VERSION 5.7 ;
  NOWIREEXTENSIONATPIN ON ;
  DIVIDERCHAR "/" ;
  BUSBITCHARS "[]" ;
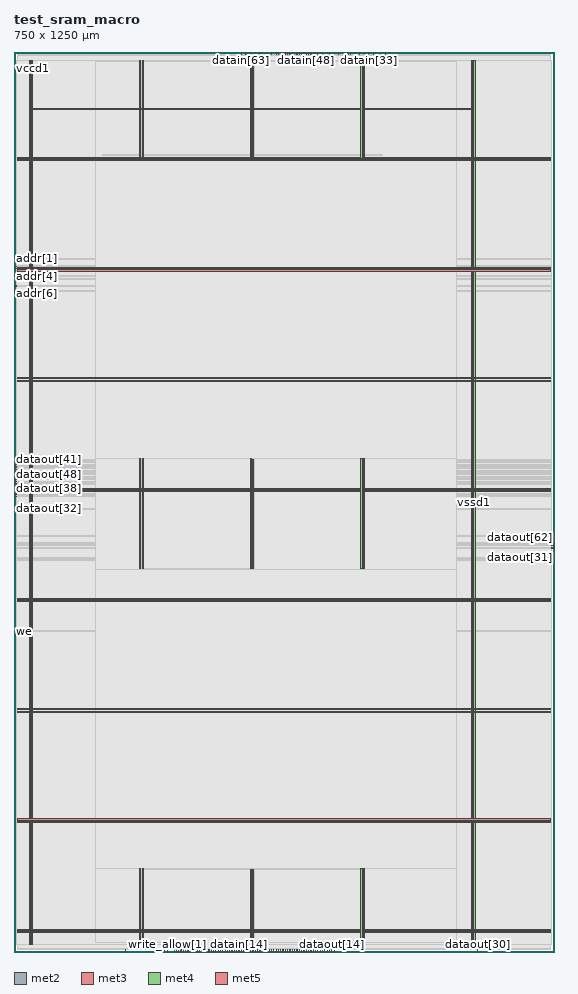
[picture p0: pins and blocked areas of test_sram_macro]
MACRO test_sram_macro
  CLASS BLOCK ;
  FOREIGN test_sram_macro ;
  ORIGIN 0.000 0.000 ;
  SIZE 750.000 BY 1250.000 ;
  PIN addr[0]
    DIRECTION INPUT ;
    USE SIGNAL ;
    ANTENNAGATEAREA 0.852000 ;
    PORT
      LAYER met2 ;
        RECT 202.950 0.000 203.230 4.000 ;
    END
  END addr[0]
  PIN addr[1]
    DIRECTION INPUT ;
    USE SIGNAL ;
    ANTENNAGATEAREA 0.495000 ;
    PORT
      LAYER met3 ;
        RECT 0.000 962.240 4.000 962.840 ;
    END
  END addr[1]
  PIN addr[2]
    DIRECTION INPUT ;
    USE SIGNAL ;
    ANTENNAGATEAREA 0.495000 ;
    PORT
      LAYER met3 ;
        RECT 0.000 952.040 4.000 952.640 ;
    END
  END addr[2]
  PIN addr[3]
    DIRECTION INPUT ;
    USE SIGNAL ;
    ANTENNAGATEAREA 0.495000 ;
    PORT
      LAYER met3 ;
        RECT 0.000 948.640 4.000 949.240 ;
    END
  END addr[3]
  PIN addr[4]
    DIRECTION INPUT ;
    USE SIGNAL ;
    ANTENNAGATEAREA 0.495000 ;
    PORT
      LAYER met3 ;
        RECT 0.000 938.440 4.000 939.040 ;
    END
  END addr[4]
  PIN addr[5]
    DIRECTION INPUT ;
    USE SIGNAL ;
    ANTENNAGATEAREA 0.495000 ;
    PORT
      LAYER met3 ;
        RECT 0.000 935.040 4.000 935.640 ;
    END
  END addr[5]
  PIN addr[6]
    DIRECTION INPUT ;
    USE SIGNAL ;
    ANTENNAGATEAREA 0.495000 ;
    PORT
      LAYER met3 ;
        RECT 0.000 924.840 4.000 925.440 ;
    END
  END addr[6]
  PIN addr[7]
    DIRECTION INPUT ;
    USE SIGNAL ;
    ANTENNAGATEAREA 0.495000 ;
    PORT
      LAYER met3 ;
        RECT 0.000 918.040 4.000 918.640 ;
    END
  END addr[7]
  PIN clk
    DIRECTION INPUT ;
    USE SIGNAL ;
    ANTENNAGATEAREA 0.852000 ;
    ANTENNADIFFAREA 0.434700 ;
    PORT
      LAYER met2 ;
        RECT 154.650 0.000 154.930 4.000 ;
    END
  END clk
  PIN cs
    DIRECTION INPUT ;
    USE SIGNAL ;
    ANTENNAGATEAREA 0.742500 ;
    PORT
      LAYER met2 ;
        RECT 444.450 0.000 444.730 4.000 ;
    END
  END cs
  PIN datain[0]
    DIRECTION INPUT ;
    USE SIGNAL ;
    ANTENNAGATEAREA 0.126000 ;
    PORT
      LAYER met2 ;
        RECT 228.710 0.000 228.990 4.000 ;
    END
  END datain[0]
  PIN datain[10]
    DIRECTION INPUT ;
    USE SIGNAL ;
    ANTENNAGATEAREA 0.213000 ;
    PORT
      LAYER met2 ;
        RECT 244.810 0.000 245.090 4.000 ;
    END
  END datain[10]
  PIN datain[11]
    DIRECTION INPUT ;
    USE SIGNAL ;
    ANTENNAGATEAREA 0.126000 ;
    PORT
      LAYER met2 ;
        RECT 289.890 0.000 290.170 4.000 ;
    END
  END datain[11]
  PIN datain[12]
    DIRECTION INPUT ;
    USE SIGNAL ;
    ANTENNAGATEAREA 0.126000 ;
    PORT
      LAYER met2 ;
        RECT 296.330 0.000 296.610 4.000 ;
    END
  END datain[12]
  PIN datain[13]
    DIRECTION INPUT ;
    USE SIGNAL ;
    ANTENNAGATEAREA 0.126000 ;
    PORT
      LAYER met2 ;
        RECT 302.770 0.000 303.050 4.000 ;
    END
  END datain[13]
  PIN datain[14]
    DIRECTION INPUT ;
    USE SIGNAL ;
    ANTENNAGATEAREA 0.126000 ;
    PORT
      LAYER met2 ;
        RECT 312.430 0.000 312.710 4.000 ;
    END
  END datain[14]
  PIN datain[15]
    DIRECTION INPUT ;
    USE SIGNAL ;
    ANTENNAGATEAREA 0.126000 ;
    PORT
      LAYER met2 ;
        RECT 318.870 0.000 319.150 4.000 ;
    END
  END datain[15]
  PIN datain[16]
    DIRECTION INPUT ;
    USE SIGNAL ;
    ANTENNAGATEAREA 0.126000 ;
    PORT
      LAYER met2 ;
        RECT 325.310 0.000 325.590 4.000 ;
    END
  END datain[16]
  PIN datain[17]
    DIRECTION INPUT ;
    USE SIGNAL ;
    ANTENNAGATEAREA 0.126000 ;
    PORT
      LAYER met2 ;
        RECT 331.750 0.000 332.030 4.000 ;
    END
  END datain[17]
  PIN datain[18]
    DIRECTION INPUT ;
    USE SIGNAL ;
    ANTENNAGATEAREA 0.126000 ;
    PORT
      LAYER met2 ;
        RECT 341.410 0.000 341.690 4.000 ;
    END
  END datain[18]
  PIN datain[19]
    DIRECTION INPUT ;
    USE SIGNAL ;
    ANTENNAGATEAREA 0.213000 ;
    PORT
      LAYER met2 ;
        RECT 354.290 0.000 354.570 4.000 ;
    END
  END datain[19]
  PIN datain[1]
    DIRECTION INPUT ;
    USE SIGNAL ;
    ANTENNAGATEAREA 0.126000 ;
    PORT
      LAYER met2 ;
        RECT 235.150 0.000 235.430 4.000 ;
    END
  END datain[1]
  PIN datain[20]
    DIRECTION INPUT ;
    USE SIGNAL ;
    ANTENNAGATEAREA 0.126000 ;
    PORT
      LAYER met2 ;
        RECT 351.070 0.000 351.350 4.000 ;
    END
  END datain[20]
  PIN datain[21]
    DIRECTION INPUT ;
    USE SIGNAL ;
    ANTENNAGATEAREA 0.213000 ;
    PORT
      LAYER met2 ;
        RECT 438.010 0.000 438.290 4.000 ;
    END
  END datain[21]
  PIN datain[22]
    DIRECTION INPUT ;
    USE SIGNAL ;
    ANTENNAGATEAREA 0.126000 ;
    PORT
      LAYER met2 ;
        RECT 360.730 0.000 361.010 4.000 ;
    END
  END datain[22]
  PIN datain[23]
    DIRECTION INPUT ;
    USE SIGNAL ;
    ANTENNAGATEAREA 0.126000 ;
    PORT
      LAYER met2 ;
        RECT 367.170 0.000 367.450 4.000 ;
    END
  END datain[23]
  PIN datain[24]
    DIRECTION INPUT ;
    USE SIGNAL ;
    ANTENNAGATEAREA 0.213000 ;
    PORT
      LAYER met2 ;
        RECT 383.270 0.000 383.550 4.000 ;
    END
  END datain[24]
  PIN datain[25]
    DIRECTION INPUT ;
    USE SIGNAL ;
    ANTENNAGATEAREA 0.126000 ;
    PORT
      LAYER met2 ;
        RECT 380.050 0.000 380.330 4.000 ;
    END
  END datain[25]
  PIN datain[26]
    DIRECTION INPUT ;
    USE SIGNAL ;
    ANTENNAGATEAREA 0.126000 ;
    PORT
      LAYER met2 ;
        RECT 386.490 0.000 386.770 4.000 ;
    END
  END datain[26]
  PIN datain[27]
    DIRECTION INPUT ;
    USE SIGNAL ;
    ANTENNAGATEAREA 0.213000 ;
    PORT
      LAYER met2 ;
        RECT 431.570 0.000 431.850 4.000 ;
    END
  END datain[27]
  PIN datain[28]
    DIRECTION INPUT ;
    USE SIGNAL ;
    ANTENNAGATEAREA 0.126000 ;
    PORT
      LAYER met2 ;
        RECT 396.150 0.000 396.430 4.000 ;
    END
  END datain[28]
  PIN datain[29]
    DIRECTION INPUT ;
    USE SIGNAL ;
    ANTENNAGATEAREA 0.126000 ;
    PORT
      LAYER met2 ;
        RECT 402.590 0.000 402.870 4.000 ;
    END
  END datain[29]
  PIN datain[2]
    DIRECTION INPUT ;
    USE SIGNAL ;
    ANTENNAGATEAREA 0.126000 ;
    PORT
      LAYER met2 ;
        RECT 241.590 0.000 241.870 4.000 ;
    END
  END datain[2]
  PIN datain[30]
    DIRECTION INPUT ;
    USE SIGNAL ;
    ANTENNAGATEAREA 0.126000 ;
    PORT
      LAYER met2 ;
        RECT 409.030 0.000 409.310 4.000 ;
    END
  END datain[30]
  PIN datain[31]
    DIRECTION INPUT ;
    USE SIGNAL ;
    ANTENNAGATEAREA 0.126000 ;
    PORT
      LAYER met2 ;
        RECT 418.690 0.000 418.970 4.000 ;
    END
  END datain[31]
  PIN datain[32]
    DIRECTION INPUT ;
    USE SIGNAL ;
    ANTENNAGATEAREA 0.213000 ;
    PORT
      LAYER met2 ;
        RECT 499.190 1246.000 499.470 1250.000 ;
    END
  END datain[32]
  PIN datain[33]
    DIRECTION INPUT ;
    USE SIGNAL ;
    ANTENNAGATEAREA 0.213000 ;
    PORT
      LAYER met2 ;
        RECT 492.750 1246.000 493.030 1250.000 ;
    END
  END datain[33]
  PIN datain[34]
    DIRECTION INPUT ;
    USE SIGNAL ;
    ANTENNAGATEAREA 0.213000 ;
    PORT
      LAYER met2 ;
        RECT 486.310 1246.000 486.590 1250.000 ;
    END
  END datain[34]
  PIN datain[35]
    DIRECTION INPUT ;
    USE SIGNAL ;
    ANTENNAGATEAREA 0.213000 ;
    PORT
      LAYER met2 ;
        RECT 479.870 1246.000 480.150 1250.000 ;
    END
  END datain[35]
  PIN datain[36]
    DIRECTION INPUT ;
    USE SIGNAL ;
    ANTENNAGATEAREA 0.213000 ;
    PORT
      LAYER met2 ;
        RECT 473.430 1246.000 473.710 1250.000 ;
    END
  END datain[36]
  PIN datain[37]
    DIRECTION INPUT ;
    USE SIGNAL ;
    ANTENNAGATEAREA 0.213000 ;
    PORT
      LAYER met2 ;
        RECT 466.990 1246.000 467.270 1250.000 ;
    END
  END datain[37]
  PIN datain[38]
    DIRECTION INPUT ;
    USE SIGNAL ;
    ANTENNAGATEAREA 0.213000 ;
    PORT
      LAYER met2 ;
        RECT 463.770 1246.000 464.050 1250.000 ;
    END
  END datain[38]
  PIN datain[39]
    DIRECTION INPUT ;
    USE SIGNAL ;
    ANTENNAGATEAREA 0.213000 ;
    PORT
      LAYER met2 ;
        RECT 457.330 1246.000 457.610 1250.000 ;
    END
  END datain[39]
  PIN datain[3]
    DIRECTION INPUT ;
    USE SIGNAL ;
    ANTENNAGATEAREA 0.126000 ;
    PORT
      LAYER met2 ;
        RECT 248.030 0.000 248.310 4.000 ;
    END
  END datain[3]
  PIN datain[40]
    DIRECTION INPUT ;
    USE SIGNAL ;
    ANTENNAGATEAREA 0.213000 ;
    PORT
      LAYER met2 ;
        RECT 450.890 1246.000 451.170 1250.000 ;
    END
  END datain[40]
  PIN datain[41]
    DIRECTION INPUT ;
    USE SIGNAL ;
    ANTENNAGATEAREA 0.213000 ;
    PORT
      LAYER met2 ;
        RECT 444.450 1246.000 444.730 1250.000 ;
    END
  END datain[41]
  PIN datain[42]
    DIRECTION INPUT ;
    USE SIGNAL ;
    ANTENNAGATEAREA 0.213000 ;
    PORT
      LAYER met2 ;
        RECT 438.010 1246.000 438.290 1250.000 ;
    END
  END datain[42]
  PIN datain[43]
    DIRECTION INPUT ;
    USE SIGNAL ;
    ANTENNAGATEAREA 0.213000 ;
    PORT
      LAYER met2 ;
        RECT 434.790 1246.000 435.070 1250.000 ;
    END
  END datain[43]
  PIN datain[44]
    DIRECTION INPUT ;
    USE SIGNAL ;
    ANTENNAGATEAREA 0.213000 ;
    PORT
      LAYER met2 ;
        RECT 428.350 1246.000 428.630 1250.000 ;
    END
  END datain[44]
  PIN datain[45]
    DIRECTION INPUT ;
    USE SIGNAL ;
    ANTENNAGATEAREA 0.213000 ;
    PORT
      LAYER met2 ;
        RECT 425.130 1246.000 425.410 1250.000 ;
    END
  END datain[45]
  PIN datain[46]
    DIRECTION INPUT ;
    USE SIGNAL ;
    ANTENNAGATEAREA 0.213000 ;
    PORT
      LAYER met2 ;
        RECT 421.910 1246.000 422.190 1250.000 ;
    END
  END datain[46]
  PIN datain[47]
    DIRECTION INPUT ;
    USE SIGNAL ;
    ANTENNAGATEAREA 0.213000 ;
    PORT
      LAYER met2 ;
        RECT 412.250 1246.000 412.530 1250.000 ;
    END
  END datain[47]
  PIN datain[48]
    DIRECTION INPUT ;
    USE SIGNAL ;
    ANTENNAGATEAREA 0.213000 ;
    PORT
      LAYER met2 ;
        RECT 405.810 1246.000 406.090 1250.000 ;
    END
  END datain[48]
  PIN datain[49]
    DIRECTION INPUT ;
    USE SIGNAL ;
    ANTENNAGATEAREA 0.213000 ;
    PORT
      LAYER met2 ;
        RECT 392.930 1246.000 393.210 1250.000 ;
    END
  END datain[49]
  PIN datain[4]
    DIRECTION INPUT ;
    USE SIGNAL ;
    ANTENNAGATEAREA 0.126000 ;
    PORT
      LAYER met2 ;
        RECT 254.470 0.000 254.750 4.000 ;
    END
  END datain[4]
  PIN datain[50]
    DIRECTION INPUT ;
    USE SIGNAL ;
    ANTENNAGATEAREA 0.213000 ;
    PORT
      LAYER met2 ;
        RECT 370.390 1246.000 370.670 1250.000 ;
    END
  END datain[50]
  PIN datain[51]
    DIRECTION INPUT ;
    USE SIGNAL ;
    ANTENNAGATEAREA 0.213000 ;
    PORT
      LAYER met2 ;
        RECT 380.050 1246.000 380.330 1250.000 ;
    END
  END datain[51]
  PIN datain[52]
    DIRECTION INPUT ;
    USE SIGNAL ;
    ANTENNAGATEAREA 0.213000 ;
    PORT
      LAYER met2 ;
        RECT 376.830 1246.000 377.110 1250.000 ;
    END
  END datain[52]
  PIN datain[53]
    DIRECTION INPUT ;
    USE SIGNAL ;
    ANTENNAGATEAREA 0.213000 ;
    PORT
      LAYER met2 ;
        RECT 373.610 1246.000 373.890 1250.000 ;
    END
  END datain[53]
  PIN datain[54]
    DIRECTION INPUT ;
    USE SIGNAL ;
    ANTENNAGATEAREA 0.213000 ;
    PORT
      LAYER met2 ;
        RECT 367.170 1246.000 367.450 1250.000 ;
    END
  END datain[54]
  PIN datain[55]
    DIRECTION INPUT ;
    USE SIGNAL ;
    ANTENNAGATEAREA 0.213000 ;
    PORT
      LAYER met2 ;
        RECT 363.950 1246.000 364.230 1250.000 ;
    END
  END datain[55]
  PIN datain[56]
    DIRECTION INPUT ;
    USE SIGNAL ;
    ANTENNAGATEAREA 0.213000 ;
    PORT
      LAYER met2 ;
        RECT 357.510 1246.000 357.790 1250.000 ;
    END
  END datain[56]
  PIN datain[57]
    DIRECTION INPUT ;
    USE SIGNAL ;
    ANTENNAGATEAREA 0.213000 ;
    PORT
      LAYER met2 ;
        RECT 351.070 1246.000 351.350 1250.000 ;
    END
  END datain[57]
  PIN datain[58]
    DIRECTION INPUT ;
    USE SIGNAL ;
    ANTENNAGATEAREA 0.213000 ;
    PORT
      LAYER met2 ;
        RECT 344.630 1246.000 344.910 1250.000 ;
    END
  END datain[58]
  PIN datain[59]
    DIRECTION INPUT ;
    USE SIGNAL ;
    ANTENNAGATEAREA 0.213000 ;
    PORT
      LAYER met2 ;
        RECT 341.410 1246.000 341.690 1250.000 ;
    END
  END datain[59]
  PIN datain[5]
    DIRECTION INPUT ;
    USE SIGNAL ;
    ANTENNAGATEAREA 0.126000 ;
    PORT
      LAYER met2 ;
        RECT 260.910 0.000 261.190 4.000 ;
    END
  END datain[5]
  PIN datain[60]
    DIRECTION INPUT ;
    USE SIGNAL ;
    ANTENNAGATEAREA 0.213000 ;
    PORT
      LAYER met2 ;
        RECT 334.970 1246.000 335.250 1250.000 ;
    END
  END datain[60]
  PIN datain[61]
    DIRECTION INPUT ;
    USE SIGNAL ;
    ANTENNAGATEAREA 0.213000 ;
    PORT
      LAYER met2 ;
        RECT 328.530 1246.000 328.810 1250.000 ;
    END
  END datain[61]
  PIN datain[62]
    DIRECTION INPUT ;
    USE SIGNAL ;
    ANTENNAGATEAREA 0.213000 ;
    PORT
      LAYER met2 ;
        RECT 322.090 1246.000 322.370 1250.000 ;
    END
  END datain[62]
  PIN datain[63]
    DIRECTION INPUT ;
    USE SIGNAL ;
    ANTENNAGATEAREA 0.213000 ;
    PORT
      LAYER met2 ;
        RECT 315.650 1246.000 315.930 1250.000 ;
    END
  END datain[63]
  PIN datain[6]
    DIRECTION INPUT ;
    USE SIGNAL ;
    ANTENNAGATEAREA 0.126000 ;
    PORT
      LAYER met2 ;
        RECT 264.130 0.000 264.410 4.000 ;
    END
  END datain[6]
  PIN datain[7]
    DIRECTION INPUT ;
    USE SIGNAL ;
    ANTENNAGATEAREA 0.126000 ;
    PORT
      LAYER met2 ;
        RECT 267.350 0.000 267.630 4.000 ;
    END
  END datain[7]
  PIN datain[8]
    DIRECTION INPUT ;
    USE SIGNAL ;
    ANTENNAGATEAREA 0.126000 ;
    PORT
      LAYER met2 ;
        RECT 273.790 0.000 274.070 4.000 ;
    END
  END datain[8]
  PIN datain[9]
    DIRECTION INPUT ;
    USE SIGNAL ;
    ANTENNAGATEAREA 0.126000 ;
    PORT
      LAYER met2 ;
        RECT 283.450 0.000 283.730 4.000 ;
    END
  END datain[9]
  PIN dataout[0]
    DIRECTION OUTPUT TRISTATE ;
    USE SIGNAL ;
    ANTENNADIFFAREA 0.795200 ;
    PORT
      LAYER met2 ;
        RECT 280.230 0.000 280.510 4.000 ;
    END
  END dataout[0]
  PIN dataout[10]
    DIRECTION OUTPUT TRISTATE ;
    USE SIGNAL ;
    ANTENNADIFFAREA 0.795200 ;
    PORT
      LAYER met2 ;
        RECT 334.970 0.000 335.250 4.000 ;
    END
  END dataout[10]
  PIN dataout[11]
    DIRECTION OUTPUT TRISTATE ;
    USE SIGNAL ;
    ANTENNADIFFAREA 0.795200 ;
    PORT
      LAYER met2 ;
        RECT 338.190 0.000 338.470 4.000 ;
    END
  END dataout[11]
  PIN dataout[12]
    DIRECTION OUTPUT TRISTATE ;
    USE SIGNAL ;
    ANTENNADIFFAREA 0.795200 ;
    PORT
      LAYER met2 ;
        RECT 344.630 0.000 344.910 4.000 ;
    END
  END dataout[12]
  PIN dataout[13]
    DIRECTION OUTPUT TRISTATE ;
    USE SIGNAL ;
    ANTENNADIFFAREA 0.795200 ;
    PORT
      LAYER met2 ;
        RECT 347.850 0.000 348.130 4.000 ;
    END
  END dataout[13]
  PIN dataout[14]
    DIRECTION OUTPUT TRISTATE ;
    USE SIGNAL ;
    ANTENNADIFFAREA 0.795200 ;
    PORT
      LAYER met2 ;
        RECT 441.230 0.000 441.510 4.000 ;
    END
  END dataout[14]
  PIN dataout[15]
    DIRECTION OUTPUT TRISTATE ;
    USE SIGNAL ;
    ANTENNADIFFAREA 0.795200 ;
    PORT
      LAYER met2 ;
        RECT 357.510 0.000 357.790 4.000 ;
    END
  END dataout[15]
  PIN dataout[16]
    DIRECTION OUTPUT TRISTATE ;
    USE SIGNAL ;
    ANTENNADIFFAREA 0.795200 ;
    PORT
      LAYER met2 ;
        RECT 363.950 0.000 364.230 4.000 ;
    END
  END dataout[16]
  PIN dataout[17]
    DIRECTION OUTPUT TRISTATE ;
    USE SIGNAL ;
    ANTENNADIFFAREA 0.795200 ;
    PORT
      LAYER met2 ;
        RECT 370.390 0.000 370.670 4.000 ;
    END
  END dataout[17]
  PIN dataout[18]
    DIRECTION OUTPUT TRISTATE ;
    USE SIGNAL ;
    ANTENNADIFFAREA 0.795200 ;
    PORT
      LAYER met2 ;
        RECT 373.610 0.000 373.890 4.000 ;
    END
  END dataout[18]
  PIN dataout[19]
    DIRECTION OUTPUT TRISTATE ;
    USE SIGNAL ;
    ANTENNADIFFAREA 0.795200 ;
    PORT
      LAYER met2 ;
        RECT 376.830 0.000 377.110 4.000 ;
    END
  END dataout[19]
  PIN dataout[1]
    DIRECTION OUTPUT TRISTATE ;
    USE SIGNAL ;
    ANTENNADIFFAREA 0.795200 ;
    PORT
      LAYER met2 ;
        RECT 270.570 0.000 270.850 4.000 ;
    END
  END dataout[1]
  PIN dataout[20]
    DIRECTION OUTPUT TRISTATE ;
    USE SIGNAL ;
    ANTENNADIFFAREA 0.795200 ;
    PORT
      LAYER met2 ;
        RECT 389.710 0.000 389.990 4.000 ;
    END
  END dataout[20]
  PIN dataout[21]
    DIRECTION OUTPUT TRISTATE ;
    USE SIGNAL ;
    ANTENNADIFFAREA 0.795200 ;
    PORT
      LAYER met2 ;
        RECT 392.930 0.000 393.210 4.000 ;
    END
  END dataout[21]
  PIN dataout[22]
    DIRECTION OUTPUT TRISTATE ;
    USE SIGNAL ;
    ANTENNADIFFAREA 0.795200 ;
    PORT
      LAYER met2 ;
        RECT 399.370 0.000 399.650 4.000 ;
    END
  END dataout[22]
  PIN dataout[23]
    DIRECTION OUTPUT TRISTATE ;
    USE SIGNAL ;
    ANTENNADIFFAREA 0.795200 ;
    PORT
      LAYER met2 ;
        RECT 405.810 0.000 406.090 4.000 ;
    END
  END dataout[23]
  PIN dataout[24]
    DIRECTION OUTPUT TRISTATE ;
    USE SIGNAL ;
    ANTENNADIFFAREA 0.795200 ;
    PORT
      LAYER met2 ;
        RECT 412.250 0.000 412.530 4.000 ;
    END
  END dataout[24]
  PIN dataout[25]
    DIRECTION OUTPUT TRISTATE ;
    USE SIGNAL ;
    ANTENNADIFFAREA 0.795200 ;
    PORT
      LAYER met2 ;
        RECT 415.470 0.000 415.750 4.000 ;
    END
  END dataout[25]
  PIN dataout[26]
    DIRECTION OUTPUT TRISTATE ;
    USE SIGNAL ;
    ANTENNADIFFAREA 0.795200 ;
    PORT
      LAYER met2 ;
        RECT 421.910 0.000 422.190 4.000 ;
    END
  END dataout[26]
  PIN dataout[27]
    DIRECTION OUTPUT TRISTATE ;
    USE SIGNAL ;
    ANTENNADIFFAREA 0.795200 ;
    PORT
      LAYER met2 ;
        RECT 428.350 0.000 428.630 4.000 ;
    END
  END dataout[27]
  PIN dataout[28]
    DIRECTION OUTPUT TRISTATE ;
    USE SIGNAL ;
    ANTENNADIFFAREA 0.795200 ;
    PORT
      LAYER met2 ;
        RECT 425.130 0.000 425.410 4.000 ;
    END
  END dataout[28]
  PIN dataout[29]
    DIRECTION OUTPUT TRISTATE ;
    USE SIGNAL ;
    ANTENNADIFFAREA 0.795200 ;
    PORT
      LAYER met2 ;
        RECT 434.790 0.000 435.070 4.000 ;
    END
  END dataout[29]
  PIN dataout[2]
    DIRECTION OUTPUT TRISTATE ;
    USE SIGNAL ;
    ANTENNADIFFAREA 0.795200 ;
    PORT
      LAYER met2 ;
        RECT 277.010 0.000 277.290 4.000 ;
    END
  END dataout[2]
  PIN dataout[30]
    DIRECTION OUTPUT TRISTATE ;
    USE SIGNAL ;
    ANTENNADIFFAREA 0.795200 ;
    PORT
      LAYER met2 ;
        RECT 644.090 0.000 644.370 4.000 ;
    END
  END dataout[30]
  PIN dataout[31]
    DIRECTION OUTPUT TRISTATE ;
    USE SIGNAL ;
    ANTENNADIFFAREA 0.445500 ;
    PORT
      LAYER met3 ;
        RECT 746.000 547.440 750.000 548.040 ;
    END
  END dataout[31]
  PIN dataout[32]
    DIRECTION OUTPUT TRISTATE ;
    USE SIGNAL ;
    ANTENNADIFFAREA 0.795200 ;
    PORT
      LAYER met3 ;
        RECT 0.000 615.440 4.000 616.040 ;
    END
  END dataout[32]
  PIN dataout[33]
    DIRECTION OUTPUT TRISTATE ;
    USE SIGNAL ;
    ANTENNADIFFAREA 0.795200 ;
    PORT
      LAYER met2 ;
        RECT 257.690 0.000 257.970 4.000 ;
    END
  END dataout[33]
  PIN dataout[34]
    DIRECTION OUTPUT TRISTATE ;
    USE SIGNAL ;
    ANTENNADIFFAREA 0.795200 ;
    PORT
      LAYER met2 ;
        RECT 238.370 0.000 238.650 4.000 ;
    END
  END dataout[34]
  PIN dataout[35]
    DIRECTION OUTPUT TRISTATE ;
    USE SIGNAL ;
    ANTENNADIFFAREA 0.795200 ;
    PORT
      LAYER met2 ;
        RECT 231.930 0.000 232.210 4.000 ;
    END
  END dataout[35]
  PIN dataout[36]
    DIRECTION OUTPUT TRISTATE ;
    USE SIGNAL ;
    ANTENNADIFFAREA 0.795200 ;
    PORT
      LAYER met2 ;
        RECT 322.090 0.000 322.370 4.000 ;
    END
  END dataout[36]
  PIN dataout[37]
    DIRECTION OUTPUT TRISTATE ;
    USE SIGNAL ;
    ANTENNADIFFAREA 0.795200 ;
    PORT
      LAYER met2 ;
        RECT 328.530 0.000 328.810 4.000 ;
    END
  END dataout[37]
  PIN dataout[38]
    DIRECTION OUTPUT TRISTATE ;
    USE SIGNAL ;
    ANTENNADIFFAREA 0.795200 ;
    PORT
      LAYER met3 ;
        RECT 0.000 632.440 4.000 633.040 ;
    END
  END dataout[38]
  PIN dataout[39]
    DIRECTION OUTPUT TRISTATE ;
    USE SIGNAL ;
    ANTENNADIFFAREA 0.795200 ;
    PORT
      LAYER met3 ;
        RECT 0.000 635.840 4.000 636.440 ;
    END
  END dataout[39]
  PIN dataout[3]
    DIRECTION OUTPUT TRISTATE ;
    USE SIGNAL ;
    ANTENNADIFFAREA 0.795200 ;
    PORT
      LAYER met2 ;
        RECT 286.670 0.000 286.950 4.000 ;
    END
  END dataout[3]
  PIN dataout[40]
    DIRECTION OUTPUT TRISTATE ;
    USE SIGNAL ;
    ANTENNADIFFAREA 0.795200 ;
    PORT
      LAYER met3 ;
        RECT 0.000 649.440 4.000 650.040 ;
    END
  END dataout[40]
  PIN dataout[41]
    DIRECTION OUTPUT TRISTATE ;
    USE SIGNAL ;
    ANTENNADIFFAREA 0.795200 ;
    PORT
      LAYER met3 ;
        RECT 0.000 683.440 4.000 684.040 ;
    END
  END dataout[41]
  PIN dataout[42]
    DIRECTION OUTPUT TRISTATE ;
    USE SIGNAL ;
    ANTENNADIFFAREA 0.795200 ;
    PORT
      LAYER met3 ;
        RECT 0.000 680.040 4.000 680.640 ;
    END
  END dataout[42]
  PIN dataout[43]
    DIRECTION OUTPUT TRISTATE ;
    USE SIGNAL ;
    ANTENNADIFFAREA 0.795200 ;
    PORT
      LAYER met3 ;
        RECT 0.000 669.840 4.000 670.440 ;
    END
  END dataout[43]
  PIN dataout[44]
    DIRECTION OUTPUT TRISTATE ;
    USE SIGNAL ;
    ANTENNADIFFAREA 0.795200 ;
    PORT
      LAYER met3 ;
        RECT 0.000 673.240 4.000 673.840 ;
    END
  END dataout[44]
  PIN dataout[45]
    DIRECTION OUTPUT TRISTATE ;
    USE SIGNAL ;
    ANTENNADIFFAREA 0.795200 ;
    PORT
      LAYER met3 ;
        RECT 0.000 676.640 4.000 677.240 ;
    END
  END dataout[45]
  PIN dataout[46]
    DIRECTION OUTPUT TRISTATE ;
    USE SIGNAL ;
    ANTENNADIFFAREA 0.795200 ;
    PORT
      LAYER met3 ;
        RECT 0.000 666.440 4.000 667.040 ;
    END
  END dataout[46]
  PIN dataout[47]
    DIRECTION OUTPUT TRISTATE ;
    USE SIGNAL ;
    ANTENNADIFFAREA 0.795200 ;
    PORT
      LAYER met3 ;
        RECT 0.000 659.640 4.000 660.240 ;
    END
  END dataout[47]
  PIN dataout[48]
    DIRECTION OUTPUT TRISTATE ;
    USE SIGNAL ;
    ANTENNADIFFAREA 0.795200 ;
    PORT
      LAYER met3 ;
        RECT 0.000 663.040 4.000 663.640 ;
    END
  END dataout[48]
  PIN dataout[49]
    DIRECTION OUTPUT TRISTATE ;
    USE SIGNAL ;
    ANTENNADIFFAREA 0.795200 ;
    PORT
      LAYER met3 ;
        RECT 0.000 656.240 4.000 656.840 ;
    END
  END dataout[49]
  PIN dataout[4]
    DIRECTION OUTPUT TRISTATE ;
    USE SIGNAL ;
    ANTENNADIFFAREA 0.795200 ;
    PORT
      LAYER met2 ;
        RECT 293.110 0.000 293.390 4.000 ;
    END
  END dataout[4]
  PIN dataout[50]
    DIRECTION OUTPUT TRISTATE ;
    USE SIGNAL ;
    ANTENNADIFFAREA 0.795200 ;
    PORT
      LAYER met3 ;
        RECT 0.000 652.840 4.000 653.440 ;
    END
  END dataout[50]
  PIN dataout[51]
    DIRECTION OUTPUT TRISTATE ;
    USE SIGNAL ;
    ANTENNADIFFAREA 0.795200 ;
    PORT
      LAYER met2 ;
        RECT 386.490 1246.000 386.770 1250.000 ;
    END
  END dataout[51]
  PIN dataout[52]
    DIRECTION OUTPUT TRISTATE ;
    USE SIGNAL ;
    ANTENNADIFFAREA 0.795200 ;
    PORT
      LAYER met2 ;
        RECT 389.710 1246.000 389.990 1250.000 ;
    END
  END dataout[52]
  PIN dataout[53]
    DIRECTION OUTPUT TRISTATE ;
    USE SIGNAL ;
    ANTENNADIFFAREA 0.795200 ;
    PORT
      LAYER met2 ;
        RECT 383.270 1246.000 383.550 1250.000 ;
    END
  END dataout[53]
  PIN dataout[54]
    DIRECTION OUTPUT TRISTATE ;
    USE SIGNAL ;
    ANTENNADIFFAREA 0.795200 ;
    PORT
      LAYER met2 ;
        RECT 402.590 1246.000 402.870 1250.000 ;
    END
  END dataout[54]
  PIN dataout[55]
    DIRECTION OUTPUT TRISTATE ;
    USE SIGNAL ;
    ANTENNADIFFAREA 0.795200 ;
    PORT
      LAYER met2 ;
        RECT 399.370 1246.000 399.650 1250.000 ;
    END
  END dataout[55]
  PIN dataout[56]
    DIRECTION OUTPUT TRISTATE ;
    USE SIGNAL ;
    ANTENNADIFFAREA 0.795200 ;
    PORT
      LAYER met2 ;
        RECT 396.150 1246.000 396.430 1250.000 ;
    END
  END dataout[56]
  PIN dataout[57]
    DIRECTION OUTPUT TRISTATE ;
    USE SIGNAL ;
    ANTENNADIFFAREA 0.795200 ;
    PORT
      LAYER met2 ;
        RECT 409.030 1246.000 409.310 1250.000 ;
    END
  END dataout[57]
  PIN dataout[58]
    DIRECTION OUTPUT TRISTATE ;
    USE SIGNAL ;
    ANTENNADIFFAREA 0.795200 ;
    PORT
      LAYER met2 ;
        RECT 418.690 1246.000 418.970 1250.000 ;
    END
  END dataout[58]
  PIN dataout[59]
    DIRECTION OUTPUT TRISTATE ;
    USE SIGNAL ;
    ANTENNADIFFAREA 0.795200 ;
    PORT
      LAYER met2 ;
        RECT 415.470 1246.000 415.750 1250.000 ;
    END
  END dataout[59]
  PIN dataout[5]
    DIRECTION OUTPUT TRISTATE ;
    USE SIGNAL ;
    ANTENNADIFFAREA 0.795200 ;
    PORT
      LAYER met2 ;
        RECT 299.550 0.000 299.830 4.000 ;
    END
  END dataout[5]
  PIN dataout[60]
    DIRECTION OUTPUT TRISTATE ;
    USE SIGNAL ;
    ANTENNADIFFAREA 0.795200 ;
    PORT
      LAYER met3 ;
        RECT 746.000 578.040 750.000 578.640 ;
    END
  END dataout[60]
  PIN dataout[61]
    DIRECTION OUTPUT TRISTATE ;
    USE SIGNAL ;
    ANTENNADIFFAREA 0.445500 ;
    PORT
      LAYER met3 ;
        RECT 746.000 567.840 750.000 568.440 ;
    END
  END dataout[61]
  PIN dataout[62]
    DIRECTION OUTPUT TRISTATE ;
    USE SIGNAL ;
    ANTENNADIFFAREA 0.795200 ;
    PORT
      LAYER met3 ;
        RECT 746.000 564.440 750.000 565.040 ;
    END
  END dataout[62]
  PIN dataout[63]
    DIRECTION OUTPUT TRISTATE ;
    USE SIGNAL ;
    ANTENNADIFFAREA 0.445500 ;
    PORT
      LAYER met3 ;
        RECT 746.000 561.040 750.000 561.640 ;
    END
  END dataout[63]
  PIN dataout[6]
    DIRECTION OUTPUT TRISTATE ;
    USE SIGNAL ;
    ANTENNADIFFAREA 0.795200 ;
    PORT
      LAYER met2 ;
        RECT 305.990 0.000 306.270 4.000 ;
    END
  END dataout[6]
  PIN dataout[7]
    DIRECTION OUTPUT TRISTATE ;
    USE SIGNAL ;
    ANTENNADIFFAREA 0.795200 ;
    PORT
      LAYER met2 ;
        RECT 309.210 0.000 309.490 4.000 ;
    END
  END dataout[7]
  PIN dataout[8]
    DIRECTION OUTPUT TRISTATE ;
    USE SIGNAL ;
    ANTENNADIFFAREA 0.795200 ;
    PORT
      LAYER met2 ;
        RECT 251.250 0.000 251.530 4.000 ;
    END
  END dataout[8]
  PIN dataout[9]
    DIRECTION OUTPUT TRISTATE ;
    USE SIGNAL ;
    ANTENNADIFFAREA 0.795200 ;
    PORT
      LAYER met2 ;
        RECT 315.650 0.000 315.930 4.000 ;
    END
  END dataout[9]
  PIN rst_n
    DIRECTION INPUT ;
    USE SIGNAL ;
    ANTENNAGATEAREA 0.213000 ;
    PORT
      LAYER met3 ;
        RECT 746.000 544.040 750.000 544.640 ;
    END
  END rst_n
  PIN vccd1
    DIRECTION INOUT ;
    USE POWER ;
    PORT
      LAYER met4 ;
        RECT 21.040 10.640 22.640 1237.840 ;
    END
    PORT
      LAYER met4 ;
        RECT 174.640 10.640 176.240 115.320 ;
    END
    PORT
      LAYER met4 ;
        RECT 174.640 532.180 176.240 685.320 ;
    END
    PORT
      LAYER met4 ;
        RECT 174.640 1102.180 176.240 1237.840 ;
    END
    PORT
      LAYER met4 ;
        RECT 328.240 10.640 329.840 114.400 ;
    END
    PORT
      LAYER met4 ;
        RECT 328.240 533.100 329.840 685.320 ;
    END
    PORT
      LAYER met4 ;
        RECT 328.240 1103.100 329.840 1237.840 ;
    END
    PORT
      LAYER met4 ;
        RECT 481.840 10.640 483.440 115.320 ;
    END
    PORT
      LAYER met4 ;
        RECT 481.840 532.180 483.440 685.320 ;
    END
    PORT
      LAYER met4 ;
        RECT 481.840 1102.180 483.440 1237.840 ;
    END
    PORT
      LAYER met4 ;
        RECT 635.440 10.640 637.040 1237.840 ;
    END
    PORT
      LAYER met5 ;
        RECT 5.280 26.730 744.520 28.330 ;
    END
    PORT
      LAYER met5 ;
        RECT 5.280 179.910 744.520 181.510 ;
    END
    PORT
      LAYER met5 ;
        RECT 5.280 333.090 744.520 334.690 ;
    END
    PORT
      LAYER met5 ;
        RECT 5.280 486.270 744.520 487.870 ;
    END
    PORT
      LAYER met5 ;
        RECT 5.280 639.450 744.520 641.050 ;
    END
    PORT
      LAYER met5 ;
        RECT 5.280 792.630 744.520 794.230 ;
    END
    PORT
      LAYER met5 ;
        RECT 5.280 945.810 744.520 947.410 ;
    END
    PORT
      LAYER met5 ;
        RECT 5.280 1098.990 744.520 1100.590 ;
    END
    PORT
      LAYER met5 ;
        RECT 21.040 1170.500 637.040 1172.100 ;
    END
  END vccd1
  PIN vssd1
    DIRECTION INOUT ;
    USE GROUND ;
    PORT
      LAYER met4 ;
        RECT 24.340 10.640 25.940 1237.840 ;
    END
    PORT
      LAYER met4 ;
        RECT 177.940 10.640 179.540 115.320 ;
    END
    PORT
      LAYER met4 ;
        RECT 177.940 532.180 179.540 685.320 ;
    END
    PORT
      LAYER met4 ;
        RECT 177.940 1102.180 179.540 1237.840 ;
    END
    PORT
      LAYER met4 ;
        RECT 331.540 10.640 333.140 114.480 ;
    END
    PORT
      LAYER met4 ;
        RECT 331.540 532.180 333.140 684.400 ;
    END
    PORT
      LAYER met4 ;
        RECT 331.540 1103.100 333.140 1237.840 ;
    END
    PORT
      LAYER met4 ;
        RECT 485.140 10.640 486.740 115.320 ;
    END
    PORT
      LAYER met4 ;
        RECT 485.140 532.180 486.740 685.320 ;
    END
    PORT
      LAYER met4 ;
        RECT 485.140 1103.100 486.740 1237.840 ;
    END
    PORT
      LAYER met4 ;
        RECT 638.740 10.640 640.340 1237.840 ;
    END
    PORT
      LAYER met5 ;
        RECT 5.280 30.030 744.520 31.630 ;
    END
    PORT
      LAYER met5 ;
        RECT 5.280 183.210 744.520 184.810 ;
    END
    PORT
      LAYER met5 ;
        RECT 5.280 336.390 744.520 337.990 ;
    END
    PORT
      LAYER met5 ;
        RECT 5.280 489.570 744.520 491.170 ;
    END
    PORT
      LAYER met5 ;
        RECT 5.280 642.750 744.520 644.350 ;
    END
    PORT
      LAYER met5 ;
        RECT 5.280 795.930 744.520 797.530 ;
    END
    PORT
      LAYER met5 ;
        RECT 5.280 949.110 744.520 950.710 ;
    END
    PORT
      LAYER met5 ;
        RECT 5.280 1102.290 744.520 1103.890 ;
    END
  END vssd1
  PIN we
    DIRECTION INPUT ;
    USE SIGNAL ;
    ANTENNAGATEAREA 0.159000 ;
    PORT
      LAYER met3 ;
        RECT 0.000 445.440 4.000 446.040 ;
    END
  END we
  PIN write_allow[0]
    DIRECTION INPUT ;
    USE SIGNAL ;
    ANTENNAGATEAREA 0.126000 ;
    PORT
      LAYER met2 ;
        RECT 209.390 0.000 209.670 4.000 ;
    END
  END write_allow[0]
  PIN write_allow[1]
    DIRECTION INPUT ;
    USE SIGNAL ;
    ANTENNAGATEAREA 0.126000 ;
    PORT
      LAYER met2 ;
        RECT 212.610 0.000 212.890 4.000 ;
    END
  END write_allow[1]
  PIN write_allow[2]
    DIRECTION INPUT ;
    USE SIGNAL ;
    ANTENNAGATEAREA 0.126000 ;
    PORT
      LAYER met2 ;
        RECT 222.270 0.000 222.550 4.000 ;
    END
  END write_allow[2]
  PIN write_allow[3]
    DIRECTION INPUT ;
    USE SIGNAL ;
    ANTENNAGATEAREA 0.126000 ;
    PORT
      LAYER met2 ;
        RECT 225.490 0.000 225.770 4.000 ;
    END
  END write_allow[3]
  PIN write_allow[4]
    DIRECTION INPUT ;
    USE SIGNAL ;
    ANTENNAGATEAREA 0.213000 ;
    PORT
      LAYER met2 ;
        RECT 521.730 1246.000 522.010 1250.000 ;
    END
  END write_allow[4]
  PIN write_allow[5]
    DIRECTION INPUT ;
    USE SIGNAL ;
    ANTENNAGATEAREA 0.213000 ;
    PORT
      LAYER met2 ;
        RECT 515.290 1246.000 515.570 1250.000 ;
    END
  END write_allow[5]
  PIN write_allow[6]
    DIRECTION INPUT ;
    USE SIGNAL ;
    ANTENNAGATEAREA 0.213000 ;
    PORT
      LAYER met2 ;
        RECT 508.850 1246.000 509.130 1250.000 ;
    END
  END write_allow[6]
  PIN write_allow[7]
    DIRECTION INPUT ;
    USE SIGNAL ;
    ANTENNAGATEAREA 0.213000 ;
    PORT
      LAYER met2 ;
        RECT 502.410 1246.000 502.690 1250.000 ;
    END
  END write_allow[7]
  OBS
      LAYER li1 ;
        RECT 5.520 10.795 744.280 1237.685 ;
      LAYER met1 ;
        RECT 4.670 10.640 745.130 1237.840 ;
      LAYER met2 ;
        RECT 4.690 1245.720 315.370 1246.170 ;
        RECT 316.210 1245.720 321.810 1246.170 ;
        RECT 322.650 1245.720 328.250 1246.170 ;
        RECT 329.090 1245.720 334.690 1246.170 ;
        RECT 335.530 1245.720 341.130 1246.170 ;
        RECT 341.970 1245.720 344.350 1246.170 ;
        RECT 345.190 1245.720 350.790 1246.170 ;
        RECT 351.630 1245.720 357.230 1246.170 ;
        RECT 358.070 1245.720 363.670 1246.170 ;
        RECT 364.510 1245.720 366.890 1246.170 ;
        RECT 367.730 1245.720 370.110 1246.170 ;
        RECT 370.950 1245.720 373.330 1246.170 ;
        RECT 374.170 1245.720 376.550 1246.170 ;
        RECT 377.390 1245.720 379.770 1246.170 ;
        RECT 380.610 1245.720 382.990 1246.170 ;
        RECT 383.830 1245.720 386.210 1246.170 ;
        RECT 387.050 1245.720 389.430 1246.170 ;
        RECT 390.270 1245.720 392.650 1246.170 ;
        RECT 393.490 1245.720 395.870 1246.170 ;
        RECT 396.710 1245.720 399.090 1246.170 ;
        RECT 399.930 1245.720 402.310 1246.170 ;
        RECT 403.150 1245.720 405.530 1246.170 ;
        RECT 406.370 1245.720 408.750 1246.170 ;
        RECT 409.590 1245.720 411.970 1246.170 ;
        RECT 412.810 1245.720 415.190 1246.170 ;
        RECT 416.030 1245.720 418.410 1246.170 ;
        RECT 419.250 1245.720 421.630 1246.170 ;
        RECT 422.470 1245.720 424.850 1246.170 ;
        RECT 425.690 1245.720 428.070 1246.170 ;
        RECT 428.910 1245.720 434.510 1246.170 ;
        RECT 435.350 1245.720 437.730 1246.170 ;
        RECT 438.570 1245.720 444.170 1246.170 ;
        RECT 445.010 1245.720 450.610 1246.170 ;
        RECT 451.450 1245.720 457.050 1246.170 ;
        RECT 457.890 1245.720 463.490 1246.170 ;
        RECT 464.330 1245.720 466.710 1246.170 ;
        RECT 467.550 1245.720 473.150 1246.170 ;
        RECT 473.990 1245.720 479.590 1246.170 ;
        RECT 480.430 1245.720 486.030 1246.170 ;
        RECT 486.870 1245.720 492.470 1246.170 ;
        RECT 493.310 1245.720 498.910 1246.170 ;
        RECT 499.750 1245.720 502.130 1246.170 ;
        RECT 502.970 1245.720 508.570 1246.170 ;
        RECT 509.410 1245.720 515.010 1246.170 ;
        RECT 515.850 1245.720 521.450 1246.170 ;
        RECT 522.290 1245.720 745.110 1246.170 ;
        RECT 4.690 4.280 745.110 1245.720 ;
        RECT 4.690 3.670 154.370 4.280 ;
        RECT 155.210 3.670 202.670 4.280 ;
        RECT 203.510 3.670 209.110 4.280 ;
        RECT 209.950 3.670 212.330 4.280 ;
        RECT 213.170 3.670 221.990 4.280 ;
        RECT 222.830 3.670 225.210 4.280 ;
        RECT 226.050 3.670 228.430 4.280 ;
        RECT 229.270 3.670 231.650 4.280 ;
        RECT 232.490 3.670 234.870 4.280 ;
        RECT 235.710 3.670 238.090 4.280 ;
        RECT 238.930 3.670 241.310 4.280 ;
        RECT 242.150 3.670 244.530 4.280 ;
        RECT 245.370 3.670 247.750 4.280 ;
        RECT 248.590 3.670 250.970 4.280 ;
        RECT 251.810 3.670 254.190 4.280 ;
        RECT 255.030 3.670 257.410 4.280 ;
        RECT 258.250 3.670 260.630 4.280 ;
        RECT 261.470 3.670 263.850 4.280 ;
        RECT 264.690 3.670 267.070 4.280 ;
        RECT 267.910 3.670 270.290 4.280 ;
        RECT 271.130 3.670 273.510 4.280 ;
        RECT 274.350 3.670 276.730 4.280 ;
        RECT 277.570 3.670 279.950 4.280 ;
        RECT 280.790 3.670 283.170 4.280 ;
        RECT 284.010 3.670 286.390 4.280 ;
        RECT 287.230 3.670 289.610 4.280 ;
        RECT 290.450 3.670 292.830 4.280 ;
        RECT 293.670 3.670 296.050 4.280 ;
        RECT 296.890 3.670 299.270 4.280 ;
        RECT 300.110 3.670 302.490 4.280 ;
        RECT 303.330 3.670 305.710 4.280 ;
        RECT 306.550 3.670 308.930 4.280 ;
        RECT 309.770 3.670 312.150 4.280 ;
        RECT 312.990 3.670 315.370 4.280 ;
        RECT 316.210 3.670 318.590 4.280 ;
        RECT 319.430 3.670 321.810 4.280 ;
        RECT 322.650 3.670 325.030 4.280 ;
        RECT 325.870 3.670 328.250 4.280 ;
        RECT 329.090 3.670 331.470 4.280 ;
        RECT 332.310 3.670 334.690 4.280 ;
        RECT 335.530 3.670 337.910 4.280 ;
        RECT 338.750 3.670 341.130 4.280 ;
        RECT 341.970 3.670 344.350 4.280 ;
        RECT 345.190 3.670 347.570 4.280 ;
        RECT 348.410 3.670 350.790 4.280 ;
        RECT 351.630 3.670 354.010 4.280 ;
        RECT 354.850 3.670 357.230 4.280 ;
        RECT 358.070 3.670 360.450 4.280 ;
        RECT 361.290 3.670 363.670 4.280 ;
        RECT 364.510 3.670 366.890 4.280 ;
        RECT 367.730 3.670 370.110 4.280 ;
        RECT 370.950 3.670 373.330 4.280 ;
        RECT 374.170 3.670 376.550 4.280 ;
        RECT 377.390 3.670 379.770 4.280 ;
        RECT 380.610 3.670 382.990 4.280 ;
        RECT 383.830 3.670 386.210 4.280 ;
        RECT 387.050 3.670 389.430 4.280 ;
        RECT 390.270 3.670 392.650 4.280 ;
        RECT 393.490 3.670 395.870 4.280 ;
        RECT 396.710 3.670 399.090 4.280 ;
        RECT 399.930 3.670 402.310 4.280 ;
        RECT 403.150 3.670 405.530 4.280 ;
        RECT 406.370 3.670 408.750 4.280 ;
        RECT 409.590 3.670 411.970 4.280 ;
        RECT 412.810 3.670 415.190 4.280 ;
        RECT 416.030 3.670 418.410 4.280 ;
        RECT 419.250 3.670 421.630 4.280 ;
        RECT 422.470 3.670 424.850 4.280 ;
        RECT 425.690 3.670 428.070 4.280 ;
        RECT 428.910 3.670 431.290 4.280 ;
        RECT 432.130 3.670 434.510 4.280 ;
        RECT 435.350 3.670 437.730 4.280 ;
        RECT 438.570 3.670 440.950 4.280 ;
        RECT 441.790 3.670 444.170 4.280 ;
        RECT 445.010 3.670 643.810 4.280 ;
        RECT 644.650 3.670 745.110 4.280 ;
      LAYER met3 ;
        RECT 4.000 963.240 746.000 1237.765 ;
        RECT 4.400 961.840 746.000 963.240 ;
        RECT 4.000 953.040 746.000 961.840 ;
        RECT 4.400 951.640 746.000 953.040 ;
        RECT 4.000 949.640 746.000 951.640 ;
        RECT 4.400 948.240 746.000 949.640 ;
        RECT 4.000 939.440 746.000 948.240 ;
        RECT 4.400 938.040 746.000 939.440 ;
        RECT 4.000 936.040 746.000 938.040 ;
        RECT 4.400 934.640 746.000 936.040 ;
        RECT 4.000 925.840 746.000 934.640 ;
        RECT 4.400 924.440 746.000 925.840 ;
        RECT 4.000 919.040 746.000 924.440 ;
        RECT 4.400 917.640 746.000 919.040 ;
        RECT 4.000 684.440 746.000 917.640 ;
        RECT 4.400 683.040 746.000 684.440 ;
        RECT 4.000 681.040 746.000 683.040 ;
        RECT 4.400 679.640 746.000 681.040 ;
        RECT 4.000 677.640 746.000 679.640 ;
        RECT 4.400 676.240 746.000 677.640 ;
        RECT 4.000 674.240 746.000 676.240 ;
        RECT 4.400 672.840 746.000 674.240 ;
        RECT 4.000 670.840 746.000 672.840 ;
        RECT 4.400 669.440 746.000 670.840 ;
        RECT 4.000 667.440 746.000 669.440 ;
        RECT 4.400 666.040 746.000 667.440 ;
        RECT 4.000 664.040 746.000 666.040 ;
        RECT 4.400 662.640 746.000 664.040 ;
        RECT 4.000 660.640 746.000 662.640 ;
        RECT 4.400 659.240 746.000 660.640 ;
        RECT 4.000 657.240 746.000 659.240 ;
        RECT 4.400 655.840 746.000 657.240 ;
        RECT 4.000 653.840 746.000 655.840 ;
        RECT 4.400 652.440 746.000 653.840 ;
        RECT 4.000 650.440 746.000 652.440 ;
        RECT 4.400 649.040 746.000 650.440 ;
        RECT 4.000 636.840 746.000 649.040 ;
        RECT 4.400 635.440 746.000 636.840 ;
        RECT 4.000 633.440 746.000 635.440 ;
        RECT 4.400 632.040 746.000 633.440 ;
        RECT 4.000 616.440 746.000 632.040 ;
        RECT 4.400 615.040 746.000 616.440 ;
        RECT 4.000 579.040 746.000 615.040 ;
        RECT 4.000 577.640 745.600 579.040 ;
        RECT 4.000 568.840 746.000 577.640 ;
        RECT 4.000 567.440 745.600 568.840 ;
        RECT 4.000 565.440 746.000 567.440 ;
        RECT 4.000 564.040 745.600 565.440 ;
        RECT 4.000 562.040 746.000 564.040 ;
        RECT 4.000 560.640 745.600 562.040 ;
        RECT 4.000 548.440 746.000 560.640 ;
        RECT 4.000 547.040 745.600 548.440 ;
        RECT 4.000 545.040 746.000 547.040 ;
        RECT 4.000 543.640 745.600 545.040 ;
        RECT 4.000 446.440 746.000 543.640 ;
        RECT 4.400 445.040 746.000 446.440 ;
        RECT 4.000 10.715 746.000 445.040 ;
      LAYER met4 ;
        RECT 113.455 1101.780 174.240 1236.745 ;
        RECT 176.640 1101.780 177.540 1236.745 ;
        RECT 179.940 1102.700 327.840 1236.745 ;
        RECT 330.240 1102.700 331.140 1236.745 ;
        RECT 333.540 1102.700 481.440 1236.745 ;
        RECT 179.940 1101.780 481.440 1102.700 ;
        RECT 483.840 1102.700 484.740 1236.745 ;
        RECT 487.140 1102.700 615.185 1236.745 ;
        RECT 483.840 1101.780 615.185 1102.700 ;
        RECT 113.455 685.720 615.185 1101.780 ;
        RECT 113.455 531.780 174.240 685.720 ;
        RECT 176.640 531.780 177.540 685.720 ;
        RECT 179.940 532.700 327.840 685.720 ;
        RECT 330.240 684.800 481.440 685.720 ;
        RECT 330.240 532.700 331.140 684.800 ;
        RECT 179.940 531.780 331.140 532.700 ;
        RECT 333.540 531.780 481.440 684.800 ;
        RECT 483.840 531.780 484.740 685.720 ;
        RECT 487.140 531.780 615.185 685.720 ;
        RECT 113.455 115.720 615.185 531.780 ;
        RECT 113.455 13.095 174.240 115.720 ;
        RECT 176.640 13.095 177.540 115.720 ;
        RECT 179.940 114.880 481.440 115.720 ;
        RECT 179.940 114.800 331.140 114.880 ;
        RECT 179.940 13.095 327.840 114.800 ;
        RECT 330.240 13.095 331.140 114.800 ;
        RECT 333.540 13.095 481.440 114.880 ;
        RECT 483.840 13.095 484.740 115.720 ;
        RECT 487.140 13.095 615.185 115.720 ;
      LAYER met5 ;
        RECT 122.940 1105.900 511.860 1107.500 ;
  END
END test_sram_macro
END LIBRARY

